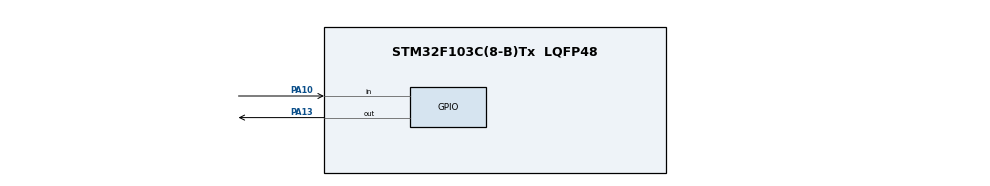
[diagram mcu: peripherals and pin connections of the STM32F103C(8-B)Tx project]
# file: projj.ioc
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Mcu.Family=STM32F1
Mcu.Name=STM32F103C(8-B)Tx
Mcu.Package=LQFP48
NVIC.PriorityGroup=NVIC_PRIORITYGROUP_4
PA10.GPIO_PuPd=GPIO_PULLUP
PA10.Signal=GPIO_Input
PA13.Signal=GPIO_Output
PD0-OSC_IN.Mode=HSE-External-Oscillator
PD0-OSC_IN.Signal=RCC_OSC_IN
PD1-OSC_OUT.Mode=HSE-External-Oscillator
PD1-OSC_OUT.Signal=RCC_OSC_OUT
ProjectManager.HeapSize=0x200
ProjectManager.StackSize=0x400
ProjectManager.TargetToolchain=STM32CubeIDE
RCC.AHBFreq_Value=72000000
RCC.APB1CLKDivider=RCC_HCLK_DIV2
RCC.APB1Freq_Value=36000000
RCC.APB1TimFreq_Value=72000000
RCC.APB2Freq_Value=72000000
RCC.APB2TimFreq_Value=72000000
RCC.HCLKFreq_Value=72000000
RCC.PLLMUL=RCC_PLL_MUL9
RCC.PLLSourceVirtual=RCC_PLLSOURCE_HSE
RCC.SYSCLKFreq_VALUE=72000000
RCC.SYSCLKSource=RCC_SYSCLKSOURCE_PLLCLK
RCC.USBFreq_Value=72000000
VP_SYS_VS_ND.Mode=No_Debug
board=custom

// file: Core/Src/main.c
/* USER CODE BEGIN Header */
/**
  ******************************************************************************
  * @file           : main.c
  * @brief          : Main program body
  ******************************************************************************
  * @attention
  *
  * Copyright (c) 2025 STMicroelectronics.
  * All rights reserved.
  *
  * This software is licensed under terms that can be found in the LICENSE file
  * in the root directory of this software component.
  * If no LICENSE file comes with this software, it is provided AS-IS.
  *
  ******************************************************************************
  */
/* USER CODE END Header */
#include "main.h"

/* USER CODE BEGIN PV */
uint8_t prevv_button_state = 1;

/* USER CODE END PV */

void SystemClock_Config(void);
static void MX_GPIO_Init(void);

int main(void)
{

  /* MCU Configuration--------------------------------------------------------*/

  /* Reset of all peripherals, Initializes the Flash interface and the Systick. */
  HAL_Init();

  /* Configure the system clock */
  SystemClock_Config();

  /* Initialize all configured peripherals */
  MX_GPIO_Init();

  /* Infinite loop */
  /* USER CODE BEGIN WHILE */
  while (1)
  {
	  GPIO_PinState current_state = HAL_GPIO_ReadPin(GPIOA, GPIO_PIN_10);

	        // --- Simplified Debounced Toggle Logic ---

	        // Checking for a press
	  	  if (current_state == GPIO_PIN_RESET)
	  	  {
	            // Check for the Rising edge
	  		  if (prevv_button_state == 1)
	  		  {
	                // debounce
	                HAL_Delay(50);

	                // Recheck
	  			  if (HAL_GPIO_ReadPin(GPIOA, GPIO_PIN_10) == GPIO_PIN_RESET)
	  			  {
	                    // toggle led
	  				  HAL_GPIO_TogglePin(GPIOA, GPIO_PIN_13);
	  				  prevv_button_state = 0;
	  			  }
	  		  }
	  	  }
	  	  else // Button is released (HIGH)
	  	  {
	            //button state released 1
	  		  prevv_button_state = 1;
	  	  }

	  	  //delay to reduce CPU usage
	  	  HAL_Delay(10);

    /* USER CODE END WHILE */

  }
}

void SystemClock_Config(void)
{
  RCC_OscInitTypeDef RCC_OscInitStruct = {0};
  RCC_ClkInitTypeDef RCC_ClkInitStruct = {0};

  /** Initializes the RCC Oscillators according to the specified parameters
  * in the RCC_OscInitTypeDef structure.
  */
  RCC_OscInitStruct.OscillatorType = RCC_OSCILLATORTYPE_HSI;
  RCC_OscInitStruct.HSIState = RCC_HSI_ON;
  RCC_OscInitStruct.HSICalibrationValue = RCC_HSICALIBRATION_DEFAULT;
  RCC_OscInitStruct.PLL.PLLState = RCC_PLL_NONE;
  if (HAL_RCC_OscConfig(&RCC_OscInitStruct) != HAL_OK)
  {
    Error_Handler();
  }

  /** Initializes the CPU, AHB and APB buses clocks
  */
  RCC_ClkInitStruct.ClockType = RCC_CLOCKTYPE_HCLK|RCC_CLOCKTYPE_SYSCLK
                              |RCC_CLOCKTYPE_PCLK1|RCC_CLOCKTYPE_PCLK2;
  RCC_ClkInitStruct.SYSCLKSource = RCC_SYSCLKSOURCE_HSI;
  RCC_ClkInitStruct.AHBCLKDivider = RCC_SYSCLK_DIV1;
  RCC_ClkInitStruct.APB1CLKDivider = RCC_HCLK_DIV1;
  RCC_ClkInitStruct.APB2CLKDivider = RCC_HCLK_DIV1;

  if (HAL_RCC_ClockConfig(&RCC_ClkInitStruct, FLASH_LATENCY_0) != HAL_OK)
  {
    Error_Handler();
  }
}

static void MX_GPIO_Init(void)
{
  GPIO_InitTypeDef GPIO_InitStruct = {0};

  /* GPIO Ports Clock Enable */
  __HAL_RCC_GPIOA_CLK_ENABLE();

  /*Configure GPIO pin Output Level */
  HAL_GPIO_WritePin(GPIOA, GPIO_PIN_13, GPIO_PIN_RESET);

  /*Configure GPIO pin : PA10 */
  GPIO_InitStruct.Pin = GPIO_PIN_10;
  GPIO_InitStruct.Mode = GPIO_MODE_INPUT;
  GPIO_InitStruct.Pull = GPIO_PULLUP;
  HAL_GPIO_Init(GPIOA, &GPIO_InitStruct);

  /*Configure GPIO pin : PA13 */
  GPIO_InitStruct.Pin = GPIO_PIN_13;
  GPIO_InitStruct.Mode = GPIO_MODE_OUTPUT_PP;
  GPIO_InitStruct.Pull = GPIO_NOPULL;
  GPIO_InitStruct.Speed = GPIO_SPEED_FREQ_LOW;
  HAL_GPIO_Init(GPIOA, &GPIO_InitStruct);

}

void Error_Handler(void)
{
  __disable_irq();
  while (1)
  {
  }
}
